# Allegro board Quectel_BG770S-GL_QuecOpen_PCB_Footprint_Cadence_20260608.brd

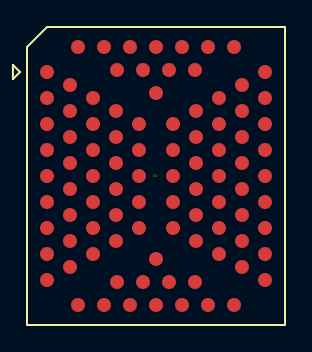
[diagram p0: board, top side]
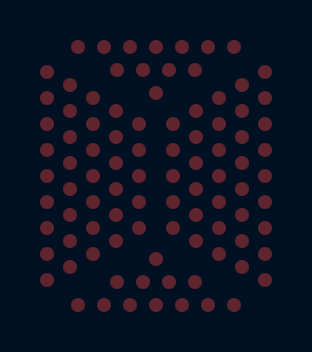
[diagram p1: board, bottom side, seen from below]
No outline. copper layers: TOP, INNER LAYER 2, INNER LAYER 3, INNER LAYER 4, INNER LAYER 5, INNER LAYER 6, INNER LAYER 7, INNER LAYER 8, INNER LAYER 9, INNER LAYER 10, INNER LAYER 11, INNER LAYER 12, INNER LAYER 13, INNER LAYER 14, INNER LAYER 15, BOTTOM. Coordinates in mm from the lowest, leftmost part position.

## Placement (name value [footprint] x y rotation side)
NOREF  -  []  0 0 0 top
U1  BG770S_QuecOpen  [BG770S_QUECOPEN]  0 0 0 top

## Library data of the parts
U1 = BG770S_QuecOpen

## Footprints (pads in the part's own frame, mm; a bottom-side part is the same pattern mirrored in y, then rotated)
BG770S_QUECOPEN
  round 0.7 smd: 1(-5.45,5.2) 2(-5.45,3.9) 3(-5.45,2.6) 4(-5.45,1.3) 5(-5.45,0) 6(-5.45,-1.3) 7(-5.45,-2.6) 8(-5.45,-3.9) 9(-5.45,-5.2) 10(-3.9,-6.45) 11(-2.6,-6.45) 12(-1.3,-6.45) 13(0,-6.45) 14(1.3,-6.45) 15(2.6,-6.45) 16(3.9,-6.45) 17(5.45,-5.2) 18(5.45,-3.9) 19(5.45,-2.6) 20(5.45,-1.3) 21(5.45,0) 22(5.45,1.3) 23(5.45,2.6) 24(5.45,3.9) 25(5.45,5.2) 26(3.9,6.45) 27(2.6,6.45) 28(1.3,6.45) 29(0,6.45) 30(-1.3,6.45) 31(-2.6,6.45) 32(-3.9,6.45) 33(-4.3,4.55) 34(-4.3,3.25) 35(-4.3,1.95) 36(-4.3,0.65) 37(-4.3,-0.65) 38(-4.3,-1.95) 39(-4.3,-3.25) 40(-4.3,-4.55) 41(-1.95,-5.3) 42(-0.65,-5.3) 43(0.65,-5.3) 44(1.95,-5.3) 45(4.3,-4.55) 46(4.3,-3.25) 47(4.3,-1.95) 48(4.3,-0.65) 49(4.3,0.65) 50(4.3,1.95) 51(4.3,3.25) 52(4.3,4.55) 53(1.95,5.3) 54(0.65,5.3) 55(-0.65,5.3) 56(-1.95,5.3) 57(-3.15,3.9) 58(-3.15,2.6) 59(-3.15,1.3) 60(-3.15,0) 61(-3.15,-1.3) 62(-3.15,-2.6) 63(-3.15,-3.9) 64(0,-4.15) 65(3.15,-3.9) 66(3.15,-2.6) 67(3.15,-1.3) 68(3.15,0) 69(3.15,1.3) 70(3.15,2.6) 71(3.15,3.9) 72(0,4.15) 73(-2,3.25) 74(-2,1.95) 75(-2,0.65) 76(-2,-0.65) 77(-2,-1.95) 78(-2,-3.25) 79(2,-3.25) 80(2,-1.95) 81(2,-0.65) 82(2,0.65) 83(2,1.95) 84(2,3.25) 85(-0.85,2.6) 86(-0.85,1.3) 87(-0.85,0) 88(-0.85,-1.3) 89(-0.85,-2.6) 90(0.85,-2.6) 91(0.85,-1.3) 92(0.85,0) 93(0.85,1.3) 94(0.85,2.6)

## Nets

Pads without a net: U1 1 2 3 4 5 6 7 8 9 10 11 12 13 14 15 16 17 18 19 20 21 22 23 24 25 26 27 28 29 30 31 32 33 34 35 36 37 38 39 40 41 42 43 44 45 46 47 48 49 50 51 52 53 54 55 56 57 58 59 60 61 62 63 64 65 66 67 68 69 70 71 72 73 74 75 76 77 78 79 80 81 82 83 84 85 86 87 88 89 90 91 92 93 94

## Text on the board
Ref Des/Silkscreen Top: REF
DISPLAY_TOP: A | B | 1 | 2 | 3 | 4
DEVICE_TYPE_TOP: DEV
COMPVAL_TYPE_TOP: VAL
